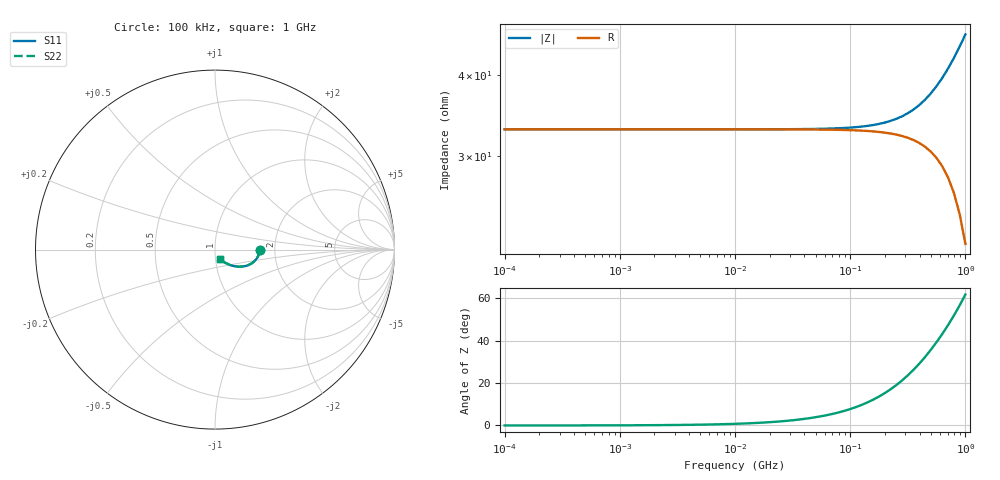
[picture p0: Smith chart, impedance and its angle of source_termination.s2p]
# Hz S RI R 50
! golden: source_termination
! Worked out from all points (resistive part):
!   81 points, 100 kHz to 1 GHz, reference 50 ohm
!   read as one part in series: R = 33 ohm at 100 kHz
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100000  0.2481 -2.49e-05  0.7519 -6.96e-05  0.7519 -6.96e-05  0.2481 -2.49e-05
501187.2  0.2481 -0.000125  0.7519 -0.000349  0.7519 -0.000349  0.2481 -0.000125
2238721  0.2481 -0.000557  0.7519 -0.00156  0.7519 -0.00156  0.2481 -0.000557
1e7  0.2481 -0.00249  0.7518 -0.00696  0.7518 -0.00696  0.2481 -0.00249
2.511886e7  0.2479 -0.00624  0.7516 -0.0175  0.7516 -0.0175  0.2479 -0.00624
5.011872e7  0.2472 -0.0124  0.7506 -0.0348  0.7506 -0.0348  0.2472 -0.0124
7.943282e7  0.2458 -0.0196  0.7487 -0.0551  0.7487 -0.0551  0.2458 -0.0196
1.122018e8  0.2436 -0.0275  0.7455 -0.0776  0.7455 -0.0776  0.2436 -0.0275
1.584893e8  0.2391 -0.0383  0.7392 -0.109  0.7392 -0.109  0.2391 -0.0383
2.238721e8  0.2304 -0.0525  0.7269 -0.152  0.7269 -0.152  0.2304 -0.0525
2.818383e8  0.2205 -0.0638  0.7127 -0.1887  0.7127 -0.1887  0.2205 -0.0638
3.162278e8  0.2137 -0.0698  0.703 -0.2096  0.703 -0.2096  0.2137 -0.0698
3.548134e8  0.2054 -0.0759  0.6911 -0.2322  0.6911 -0.2322  0.2054 -0.0759
3.981072e8  0.1952 -0.0818  0.6764 -0.2566  0.6764 -0.2566  0.1952 -0.0818
4.466836e8  0.183 -0.0872  0.6585 -0.2824  0.6585 -0.2824  0.183 -0.0872
5.011872e8  0.1684 -0.0917  0.6368 -0.3094  0.6368 -0.3094  0.1684 -0.0917
5.623413e8  0.151 -0.0946  0.6108 -0.337  0.6108 -0.337  0.151 -0.0946
6.309573e8  0.1309 -0.0952  0.5799 -0.3647  0.5799 -0.3647  0.1309 -0.0952
7.079458e8  0.1079 -0.0924  0.5438 -0.3914  0.5438 -0.3914  0.1079 -0.0924
7.943282e8  0.0824 -0.0852  0.5022 -0.4162  0.5022 -0.4162  0.0824 -0.0852
8.912509e8  0.0548 -0.0723  0.4552 -0.4375  0.4552 -0.4375  0.0548 -0.0723
1e9  0.0261 -0.0524  0.4031 -0.4542  0.4031 -0.4542  0.0261 -0.0524
